VERSION 5.7 ;
  NOWIREEXTENSIONATPIN ON ;
  DIVIDERCHAR "/" ;
  BUSBITCHARS "[]" ;
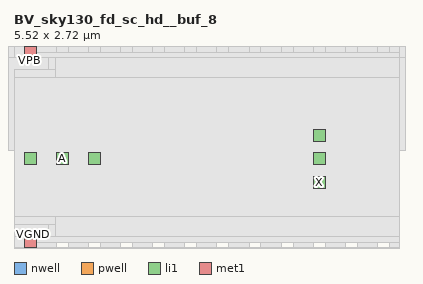
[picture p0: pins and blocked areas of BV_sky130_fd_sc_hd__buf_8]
MACRO BV_sky130_fd_sc_hd__buf_8
  CLASS BLOCK ;
  FOREIGN BV_sky130_fd_sc_hd__buf_8 ;
  ORIGIN 0.000 0.000 ;
  SIZE 5.520 BY 2.720 ;
  PIN VPB
    PORT
      LAYER nwell ;
        RECT 0.150 2.635 0.320 2.805 ;
    END
  END VPB
  PIN VNB
    PORT
      LAYER pwell ;
        RECT 0.150 -0.085 0.320 0.085 ;
    END
  END VNB
  PIN VGND
    USE GROUND ;
    PORT
      LAYER li1 ;
        RECT 0.150 -0.085 0.320 0.085 ;
    END
    PORT
      LAYER met1 ;
        RECT 0.150 -0.085 0.320 0.085 ;
    END
  END VGND
  PIN VPWR
    USE POWER ;
    PORT
      LAYER li1 ;
        RECT 0.150 2.635 0.320 2.805 ;
    END
    PORT
      LAYER met1 ;
        RECT 0.150 2.635 0.320 2.805 ;
    END
  END VPWR
  PIN A
    PORT
      LAYER li1 ;
        RECT 1.070 1.105 1.240 1.275 ;
    END
    PORT
      LAYER li1 ;
        RECT 0.610 1.105 0.780 1.275 ;
    END
    PORT
      LAYER li1 ;
        RECT 0.150 1.105 0.320 1.275 ;
    END
  END A
  PIN X
    PORT
      LAYER li1 ;
        RECT 4.290 0.765 4.460 0.935 ;
    END
    PORT
      LAYER li1 ;
        RECT 4.290 1.105 4.460 1.275 ;
    END
    PORT
      LAYER li1 ;
        RECT 4.290 1.445 4.460 1.615 ;
    END
  END X
  OBS
      LAYER nwell ;
        RECT -0.190 2.805 5.710 2.910 ;
        RECT -0.190 2.635 0.150 2.805 ;
        RECT 0.320 2.635 5.710 2.805 ;
        RECT -0.190 1.305 5.710 2.635 ;
        RECT 0.000 0.085 5.520 1.305 ;
      LAYER li1 ;
        RECT 0.000 2.635 0.145 2.805 ;
        RECT 0.320 2.720 0.605 2.805 ;
        RECT 0.775 2.720 1.065 2.805 ;
        RECT 1.235 2.720 1.525 2.805 ;
        RECT 1.695 2.720 1.985 2.805 ;
        RECT 2.155 2.720 2.445 2.805 ;
        RECT 2.615 2.720 2.905 2.805 ;
        RECT 3.075 2.720 3.365 2.805 ;
        RECT 3.535 2.720 3.825 2.805 ;
        RECT 3.995 2.720 4.285 2.805 ;
        RECT 4.455 2.720 4.745 2.805 ;
        RECT 4.915 2.720 5.205 2.805 ;
        RECT 5.375 2.720 5.520 2.805 ;
        RECT 0.320 2.635 5.520 2.720 ;
        RECT 0.490 2.465 5.520 2.635 ;
        RECT 0.000 1.785 5.520 2.465 ;
        RECT 0.000 1.445 4.120 1.785 ;
        RECT 1.410 0.935 4.120 1.445 ;
        RECT 0.000 0.595 4.120 0.935 ;
        RECT 4.630 0.595 5.520 1.785 ;
        RECT 0.000 0.255 5.520 0.595 ;
        RECT 0.490 0.085 5.520 0.255 ;
        RECT 0.000 -0.085 0.145 0.085 ;
        RECT 0.320 0.000 5.520 0.085 ;
        RECT 0.320 -0.085 0.605 0.000 ;
        RECT 0.775 -0.085 1.065 0.000 ;
        RECT 1.235 -0.085 1.525 0.000 ;
        RECT 1.695 -0.085 1.985 0.000 ;
        RECT 2.155 -0.085 2.445 0.000 ;
        RECT 2.615 -0.085 2.905 0.000 ;
        RECT 3.075 -0.085 3.365 0.000 ;
        RECT 3.535 -0.085 3.825 0.000 ;
        RECT 3.995 -0.085 4.285 0.000 ;
        RECT 4.455 -0.085 4.745 0.000 ;
        RECT 4.915 -0.085 5.205 0.000 ;
        RECT 5.375 -0.085 5.520 0.000 ;
      LAYER met1 ;
        RECT 0.000 2.805 5.520 2.960 ;
        RECT 0.000 2.635 0.145 2.805 ;
        RECT 0.320 2.720 0.605 2.805 ;
        RECT 0.775 2.720 1.065 2.805 ;
        RECT 1.235 2.720 1.525 2.805 ;
        RECT 1.695 2.720 1.985 2.805 ;
        RECT 2.155 2.720 2.445 2.805 ;
        RECT 2.615 2.720 2.905 2.805 ;
        RECT 3.075 2.720 3.365 2.805 ;
        RECT 3.535 2.720 3.825 2.805 ;
        RECT 3.995 2.720 4.285 2.805 ;
        RECT 4.455 2.720 4.745 2.805 ;
        RECT 4.915 2.720 5.205 2.805 ;
        RECT 5.375 2.720 5.520 2.805 ;
        RECT 0.320 2.635 5.520 2.720 ;
        RECT 0.600 2.355 5.520 2.635 ;
        RECT 0.000 0.365 5.520 2.355 ;
        RECT 0.600 0.085 5.520 0.365 ;
        RECT 0.000 -0.085 0.145 0.085 ;
        RECT 0.320 0.000 5.520 0.085 ;
        RECT 0.320 -0.085 0.605 0.000 ;
        RECT 0.775 -0.085 1.065 0.000 ;
        RECT 1.235 -0.085 1.525 0.000 ;
        RECT 1.695 -0.085 1.985 0.000 ;
        RECT 2.155 -0.085 2.445 0.000 ;
        RECT 2.615 -0.085 2.905 0.000 ;
        RECT 3.075 -0.085 3.365 0.000 ;
        RECT 3.535 -0.085 3.825 0.000 ;
        RECT 3.995 -0.085 4.285 0.000 ;
        RECT 4.455 -0.085 4.745 0.000 ;
        RECT 4.915 -0.085 5.205 0.000 ;
        RECT 5.375 -0.085 5.520 0.000 ;
        RECT 0.000 -0.240 5.520 -0.085 ;
  END
END BV_sky130_fd_sc_hd__buf_8
END LIBRARY

